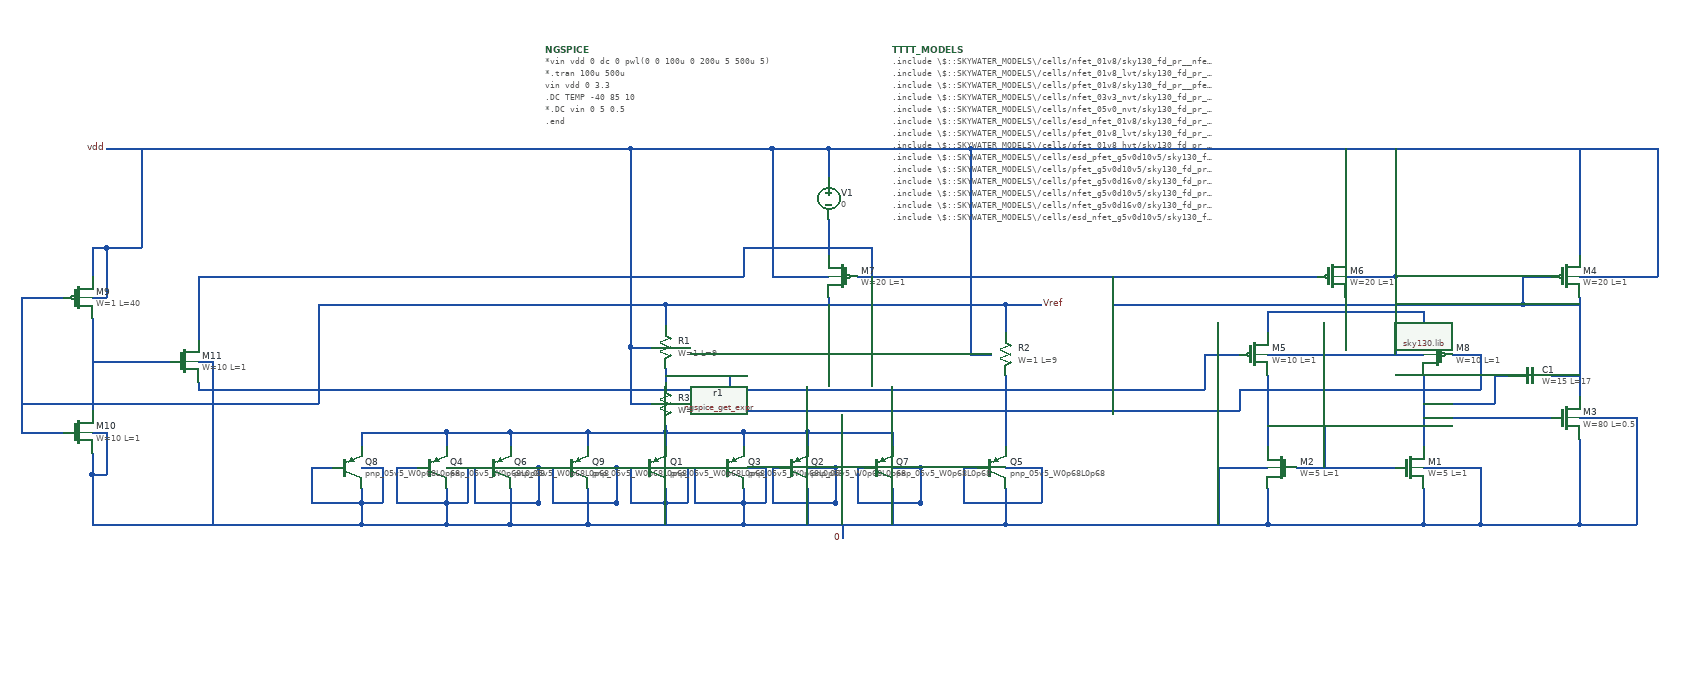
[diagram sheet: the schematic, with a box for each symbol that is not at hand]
v {xschem version=2.9.9 file_version=1.2 }
G {}
K {}
V {}
S {}
E {}
N 3560 -1290 3670 -1290 { lab=0}
N 3970 -1370 4110 -1370 { lab=#net1}
N 3930 -1470 3930 -1400 { lab=#net1}
N 4150 -1470 4150 -1400 { lab=#net2}
N 4010 -1430 4010 -1370 { lab=#net1}
N 3930 -1430 4010 -1430 { lab=#net1}
N 4150 -1340 4150 -1290 { lab=0}
N 3930 -1290 4150 -1290 { lab=0}
N 3930 -1340 3930 -1290 { lab=0}
N 4150 -1500 4150 -1470 { lab=#net2}
N 3930 -1500 3930 -1470 { lab=#net1}
N 4150 -1590 4150 -1560 { lab=#net3}
N 3930 -1590 4150 -1590 { lab=#net3}
N 3930 -1590 3930 -1560 { lab=#net3}
N 4040 -1610 4040 -1590 { lab=#net3}
N 3930 -1530 3980 -1530 { lab=vdd}
N 3980 -1530 4150 -1530 { lab=vdd}
N 4150 -1370 4190 -1370 { lab=0}
N 3810 -1290 3930 -1290 { lab=0}
N 3860 -1370 3930 -1370 { lab=0}
N 3860 -1370 3860 -1290 { lab=0}
N 4190 -1370 4230 -1370 { lab=0}
N 4230 -1370 4230 -1300 { lab=0}
N 4230 -1300 4230 -1290 { lab=0}
N 4150 -1290 4230 -1290 { lab=0}
N 4150 -1440 4330 -1440 { lab=#net2}
N 3080 -1510 3080 -1490 { lab=#net4}
N 3080 -1600 3370 -1600 { lab=Vref}
N 4370 -1410 4370 -1290 { lab=0}
N 4230 -1290 4370 -1290 { lab=0}
N 4450 -1440 4450 -1290 { lab=0}
N 4370 -1610 4370 -1470 { lab=#net5}
N 4370 -1640 4480 -1640 { lab=vdd}
N 4480 -1720 4480 -1640 { lab=vdd}
N 4370 -1720 4370 -1670 { lab=vdd}
N 4040 -1720 4040 -1670 { lab=vdd}
N 4230 -1530 4230 -1480 { lab=#net4}
N 4190 -1530 4230 -1530 { lab=#net4}
N 3840 -1530 3890 -1530 { lab=#net6}
N 3560 -1600 3610 -1600 { lab=Vref}
N 4330 -1500 4370 -1500 { lab=#net5}
N 4040 -1640 4110 -1640 { lab=vdd}
N 4110 -1640 4110 -1530 { lab=vdd}
N 4110 -1720 4110 -1640 { lab=vdd}
N 4290 -1640 4340 -1640 { lab=#net5}
N 3710 -1600 4290 -1600 { lab=#net5}
N 3080 -1600 3080 -1590 { lab=Vref}
N 3080 -1590 3080 -1570 { lab=Vref}
N 3560 -1500 3560 -1460 { lab=#net6}
N 3560 -1600 3560 -1560 { lab=Vref}
N 3190 -1370 3220 -1370 { lab=0}
N 3220 -1370 3220 -1320 { lab=0}
N 3190 -1320 3220 -1320 { lab=0}
N 3190 -1340 3190 -1320 { lab=0}
N 3190 -1320 3190 -1290 { lab=0}
N 3370 -1600 3560 -1600 { lab=Vref}
N 3560 -1460 3560 -1400 { lab=#net6}
N 3500 -1370 3520 -1370 { lab=0}
N 3500 -1370 3500 -1320 { lab=0}
N 3500 -1320 3610 -1320 { lab=0}
N 3610 -1370 3610 -1320 { lab=0}
N 3560 -1370 3610 -1370 { lab=0}
N 3560 -1340 3560 -1320 { lab=0}
N 3560 -1320 3560 -1290 { lab=0}
N 3190 -1420 3190 -1400 { lab=#net7}
N 3840 -1530 3840 -1480 { lab=#net6}
N 3890 -1480 4230 -1480 { lab=#net4}
N 3890 -1480 3890 -1450 { lab=#net4}
N 3170 -1450 3890 -1450 { lab=#net4}
N 3170 -1500 3170 -1450 { lab=#net4}
N 3080 -1500 3170 -1500 { lab=#net4}
N 3310 -1610 3310 -1600 { lab=Vref}
N 3350 -1640 4000 -1640 { lab=#net5}
N 4290 -1600 4370 -1600 { lab=#net5}
N 4290 -1640 4290 -1600 { lab=#net5}
N 4370 -1440 4450 -1440 { lab=0}
N 4370 -1290 4450 -1290 { lab=0}
N 3230 -1640 3310 -1640 { lab=vdd}
N 3230 -1720 3230 -1640 { lab=vdd}
N 3710 -1640 3710 -1600 { lab=#net5}
N 2920 -1370 2930 -1370 { lab=0}
N 2920 -1370 2920 -1320 { lab=0}
N 2920 -1320 3010 -1320 { lab=0}
N 3010 -1370 3010 -1320 { lab=0}
N 2970 -1370 3010 -1370 { lab=0}
N 2970 -1340 2970 -1320 { lab=0}
N 2970 -1320 2970 -1290 { lab=0}
N 2970 -1420 2970 -1400 { lab=#net7}
N 2970 -1420 3080 -1420 { lab=#net7}
N 3120 -1370 3150 -1370 { lab=0}
N 3120 -1370 3120 -1320 { lab=0}
N 3120 -1320 3190 -1320 { lab=0}
N 2970 -1290 3190 -1290 { lab=0}
N 3080 -1420 3190 -1420 { lab=#net7}
N 3080 -1430 3080 -1420 { lab=#net7}
N 3190 -1290 3560 -1290 { lab=0}
N 3330 -1290 3330 -1270 { lab=0}
N 3080 -1370 3110 -1370 { lab=0}
N 3110 -1370 3110 -1320 { lab=0}
N 3080 -1320 3110 -1320 { lab=0}
N 3080 -1340 3080 -1320 { lab=0}
N 3080 -1320 3080 -1290 { lab=0}
N 3080 -1420 3080 -1400 { lab=#net7}
N 3010 -1370 3010 -1320 { lab=0}
N 3030 -1370 3040 -1370 { lab=0}
N 3030 -1370 3030 -1320 { lab=0}
N 3030 -1320 3080 -1320 { lab=0}
N 3230 -1370 3240 -1370 { lab=0}
N 3230 -1370 3230 -1320 { lab=0}
N 3230 -1320 3320 -1320 { lab=0}
N 3320 -1370 3320 -1320 { lab=0}
N 3280 -1370 3320 -1370 { lab=0}
N 3280 -1340 3280 -1320 { lab=0}
N 3280 -1320 3280 -1290 { lab=0}
N 3280 -1420 3280 -1400 { lab=#net7}
N 3320 -1370 3320 -1320 { lab=0}
N 3190 -1420 3280 -1420 { lab=#net7}
N 2770 -1370 2800 -1370 { lab=0}
N 2800 -1370 2800 -1320 { lab=0}
N 2770 -1320 2800 -1320 { lab=0}
N 2770 -1340 2770 -1320 { lab=0}
N 2770 -1320 2770 -1290 { lab=0}
N 2770 -1420 2770 -1400 { lab=#net7}
N 2700 -1370 2730 -1370 { lab=0}
N 2700 -1370 2700 -1320 { lab=0}
N 2700 -1320 2770 -1320 { lab=0}
N 2810 -1370 2820 -1370 { lab=0}
N 2810 -1370 2810 -1320 { lab=0}
N 2810 -1320 2900 -1320 { lab=0}
N 2900 -1370 2900 -1320 { lab=0}
N 2860 -1370 2900 -1370 { lab=0}
N 2860 -1340 2860 -1320 { lab=0}
N 2860 -1320 2860 -1290 { lab=0}
N 2860 -1420 2860 -1400 { lab=#net7}
N 2900 -1370 2900 -1320 { lab=0}
N 2770 -1420 2860 -1420 { lab=#net7}
N 2860 -1290 2970 -1290 { lab=0}
N 2770 -1290 2860 -1290 { lab=0}
N 3350 -1370 3360 -1370 { lab=0}
N 3350 -1370 3350 -1320 { lab=0}
N 3350 -1320 3440 -1320 { lab=0}
N 3440 -1370 3440 -1320 { lab=0}
N 3400 -1370 3440 -1370 { lab=0}
N 3400 -1340 3400 -1320 { lab=0}
N 3400 -1420 3400 -1400 { lab=#net7}
N 3440 -1370 3440 -1320 { lab=0}
N 3400 -1320 3400 -1290 { lab=0}
N 3280 -1420 3400 -1420 { lab=#net7}
N 2860 -1420 2970 -1420 { lab=#net7}
N 2650 -1370 2680 -1370 { lab=0}
N 2680 -1370 2680 -1320 { lab=0}
N 2650 -1320 2680 -1320 { lab=0}
N 2650 -1340 2650 -1320 { lab=0}
N 2650 -1320 2650 -1290 { lab=0}
N 2650 -1420 2650 -1400 { lab=#net7}
N 2580 -1370 2610 -1370 { lab=0}
N 2580 -1370 2580 -1320 { lab=0}
N 2580 -1320 2650 -1320 { lab=0}
N 2650 -1420 2770 -1420 { lab=#net7}
N 2650 -1290 2770 -1290 { lab=0}
N 2170 -1610 2230 -1610 { lab=Vref}
N 2170 -1610 2170 -1420 { lab=Vref}
N 2170 -1420 2230 -1420 { lab=Vref}
N 2270 -1580 2270 -1450 { lab=#net8}
N 2270 -1610 2290 -1610 { lab=vdd}
N 2290 -1680 2290 -1610 { lab=vdd}
N 2270 -1680 2290 -1680 { lab=vdd}
N 2270 -1680 2270 -1640 { lab=vdd}
N 2270 -1420 2290 -1420 { lab=0}
N 2290 -1420 2290 -1360 { lab=0}
N 2270 -1360 2290 -1360 { lab=0}
N 2270 -1390 2270 -1360 { lab=0}
N 2270 -1360 2270 -1300 { lab=0}
N 2270 -1300 2270 -1290 { lab=0}
N 2270 -1290 2650 -1290 { lab=0}
N 2420 -1640 2420 -1550 { lab=#net5}
N 2420 -1640 3190 -1640 { lab=#net5}
N 3190 -1680 3190 -1640 { lab=#net5}
N 3190 -1680 3370 -1680 { lab=#net5}
N 3370 -1680 3370 -1640 { lab=#net5}
N 2420 -1520 2440 -1520 { lab=0}
N 2440 -1520 2440 -1290 { lab=0}
N 2420 -1460 2590 -1460 { lab=Vref}
N 2590 -1600 2590 -1460 { lab=Vref}
N 2590 -1600 3080 -1600 { lab=Vref}
N 2270 -1520 2380 -1520 { lab=#net8}
N 2170 -1460 2420 -1460 { lab=Vref}
N 2420 -1480 3560 -1480 { lab=#net6}
N 2420 -1490 2420 -1480 { lab=#net6}
N 3510 -1530 3540 -1530 { lab=vdd}
N 3510 -1720 3510 -1530 { lab=vdd}
N 3030 -1540 3060 -1540 { lab=vdd}
N 3030 -1460 3060 -1460 { lab=vdd}
N 3030 -1540 3030 -1460 { lab=vdd}
N 4150 -1460 4250 -1460 { lab=#net2}
N 4250 -1500 4250 -1460 { lab=#net2}
N 4250 -1500 4270 -1500 { lab=#net2}
N 3670 -1290 3810 -1290 { lab=0}
N 3560 -1480 3680 -1480 { lab=#net6}
N 3680 -1480 3840 -1480 { lab=#net6}
N 3030 -1820 3030 -1540 { lab=vdd}
N 2290 -1820 3030 -1820 { lab=vdd}
N 2290 -1680 2340 -1680 { lab=vdd}
N 2340 -1820 2340 -1680 { lab=vdd}
N 3230 -1820 3230 -1720 { lab=vdd}
N 3030 -1820 3230 -1820 { lab=vdd}
N 3310 -1720 3310 -1670 { lab=#net9}
N 3310 -1820 3310 -1780 { lab=vdd}
N 3230 -1820 3310 -1820 { lab=vdd}
N 3510 -1820 3510 -1720 { lab=vdd}
N 3310 -1820 3510 -1820 { lab=vdd}
N 3510 -1820 4480 -1820 { lab=vdd}
N 4480 -1820 4480 -1720 { lab=vdd}
N 4370 -1820 4370 -1720 { lab=vdd}
N 4110 -1820 4110 -1720 { lab=vdd}
N 4040 -1820 4040 -1720 { lab=vdd}
C {sky130_fd_pr/pnp_05v5.sym} 3170 -1370 0 0 {name=Q3
model=pnp_05v5_W0p68L0p68
spiceprefix=X
}
C {devices/lab_pin.sym} 3610 -1600 0 1 {name=l4 sig_type=std_logic lab=Vref}
C {devices/code_shown.sym} 2910 -1960 0 0 {name=NGSPICE
only_toplevel=true
value="
*vin vdd 0 dc 0 pwl(0 0 100u 0 200u 5 500u 5)
*.tran 100u 500u
vin vdd 0 3.3
.DC TEMP -40 85 10
*.DC vin 0 5 0.5
.end
" }
C {sky130_fd_pr/pnp_05v5.sym} 3540 -1370 0 0 {name=Q5
model=pnp_05v5_W0p68L0p68
spiceprefix=X
}
C {devices/lab_pin.sym} 2290 -1820 0 0 {name=l2 sig_type=std_logic lab=vdd}
C {sky130_fd_pr/pnp_05v5.sym} 2950 -1370 0 0 {name=Q9
model=pnp_05v5_W0p68L0p68
spiceprefix=X
}
C {devices/lab_pin.sym} 3330 -1270 0 0 {name=l1 sig_type=std_logic lab=0}
C {sky130_fd_pr/pnp_05v5.sym} 3060 -1370 0 0 {name=Q1
model=pnp_05v5_W0p68L0p68
spiceprefix=X
}
C {sky130_fd_pr/pnp_05v5.sym} 3260 -1370 0 0 {name=Q2
model=pnp_05v5_W0p68L0p68
spiceprefix=X
}
C {sky130_fd_pr/pnp_05v5.sym} 2750 -1370 0 0 {name=Q4
model=pnp_05v5_W0p68L0p68
spiceprefix=X
}
C {sky130_fd_pr/pnp_05v5.sym} 2840 -1370 0 0 {name=Q6
model=pnp_05v5_W0p68L0p68
spiceprefix=X
}
C {sky130_fd_pr/pnp_05v5.sym} 3380 -1370 0 0 {name=Q7
model=pnp_05v5_W0p68L0p68
spiceprefix=X
}
C {sky130_fd_pr/pnp_05v5.sym} 2630 -1370 0 0 {name=Q8
model=pnp_05v5_W0p68L0p68
spiceprefix=X
}
C {sky130_fd_pr/nfet_g5v0d10v5.sym} 4130 -1370 0 0 {name=M1
L=1
W=5
nf=1
mult=1
ad="'int((nf+1)/2) * W/nf * 0.29'" 
pd="'2*int((nf+1)/2) * (W/nf + 0.29)'"
as="'int((nf+2)/2) * W/nf * 0.29'" 
ps="'2*int((nf+2)/2) * (W/nf + 0.29)'"
nrd="'0.29 / W'" nrs="'0.29 / W'"
sa=0 sb=0 sd=0
model=nfet_g5v0d10v5
spiceprefix=X
}
C {sky130_fd_pr/nfet_g5v0d10v5.sym} 3950 -1370 0 1 {name=M2
L=1
W=5
nf=1
mult=1
ad="'int((nf+1)/2) * W/nf * 0.29'" 
pd="'2*int((nf+1)/2) * (W/nf + 0.29)'"
as="'int((nf+2)/2) * W/nf * 0.29'" 
ps="'2*int((nf+2)/2) * (W/nf + 0.29)'"
nrd="'0.29 / W'" nrs="'0.29 / W'"
sa=0 sb=0 sd=0
model=nfet_g5v0d10v5
spiceprefix=X
}
C {sky130_fd_pr/nfet_g5v0d10v5.sym} 4350 -1440 0 0 {name=M3
L=0.5
W=80
nf=1
mult=10
ad="'int((nf+1)/2) * W/nf * 0.29'" 
pd="'2*int((nf+1)/2) * (W/nf + 0.29)'"
as="'int((nf+2)/2) * W/nf * 0.29'" 
ps="'2*int((nf+2)/2) * (W/nf + 0.29)'"
nrd="'0.29 / W'" nrs="'0.29 / W'"
sa=0 sb=0 sd=0
model=nfet_g5v0d10v5
spiceprefix=X
}
C {sky130_fd_pr/pfet_g5v0d10v5.sym} 4350 -1640 0 0 {name=M4
L=1
W=20
nf=1
mult=1
ad="'int((nf+1)/2) * W/nf * 0.29'" 
pd="'2*int((nf+1)/2) * (W/nf + 0.29)'"
as="'int((nf+2)/2) * W/nf * 0.29'" 
ps="'2*int((nf+2)/2) * (W/nf + 0.29)'"
nrd="'0.29 / W'" nrs="'0.29 / W'"
sa=0 sb=0 sd=0
model=pfet_g5v0d10v5
spiceprefix=X
}
C {sky130_fd_pr/pfet_g5v0d10v5.sym} 3910 -1530 0 0 {name=M5
L=1
W=10
nf=1
mult=1
ad="'int((nf+1)/2) * W/nf * 0.29'" 
pd="'2*int((nf+1)/2) * (W/nf + 0.29)'"
as="'int((nf+2)/2) * W/nf * 0.29'" 
ps="'2*int((nf+2)/2) * (W/nf + 0.29)'"
nrd="'0.29 / W'" nrs="'0.29 / W'"
sa=0 sb=0 sd=0
model=pfet_g5v0d10v5
spiceprefix=X
}
C {sky130_fd_pr/pfet_g5v0d10v5.sym} 4020 -1640 0 0 {name=M6
L=1
W=20
nf=1
mult=1
ad="'int((nf+1)/2) * W/nf * 0.29'" 
pd="'2*int((nf+1)/2) * (W/nf + 0.29)'"
as="'int((nf+2)/2) * W/nf * 0.29'" 
ps="'2*int((nf+2)/2) * (W/nf + 0.29)'"
nrd="'0.29 / W'" nrs="'0.29 / W'"
sa=0 sb=0 sd=0
model=pfet_g5v0d10v5
spiceprefix=X
}
C {sky130_fd_pr/pfet_g5v0d10v5.sym} 3330 -1640 0 1 {name=M7
L=1
W=20
nf=1
mult=1
ad="'int((nf+1)/2) * W/nf * 0.29'" 
pd="'2*int((nf+1)/2) * (W/nf + 0.29)'"
as="'int((nf+2)/2) * W/nf * 0.29'" 
ps="'2*int((nf+2)/2) * (W/nf + 0.29)'"
nrd="'0.29 / W'" nrs="'0.29 / W'"
sa=0 sb=0 sd=0
model=pfet_g5v0d10v5
spiceprefix=X
}
C {sky130_fd_pr/pfet_g5v0d10v5.sym} 4170 -1530 0 1 {name=M8
L=1
W=10
nf=1
mult=1
ad="'int((nf+1)/2) * W/nf * 0.29'" 
pd="'2*int((nf+1)/2) * (W/nf + 0.29)'"
as="'int((nf+2)/2) * W/nf * 0.29'" 
ps="'2*int((nf+2)/2) * (W/nf + 0.29)'"
nrd="'0.29 / W'" nrs="'0.29 / W'"
sa=0 sb=0 sd=0
model=pfet_g5v0d10v5
spiceprefix=X
}
C {sky130_fd_pr/pfet_g5v0d10v5.sym} 2250 -1610 0 0 {name=M9
L=40
W=1
nf=1
mult=1
ad="'int((nf+1)/2) * W/nf * 0.29'" 
pd="'2*int((nf+1)/2) * (W/nf + 0.29)'"
as="'int((nf+2)/2) * W/nf * 0.29'" 
ps="'2*int((nf+2)/2) * (W/nf + 0.29)'"
nrd="'0.29 / W'" nrs="'0.29 / W'"
sa=0 sb=0 sd=0
model=pfet_g5v0d10v5
spiceprefix=X
}
C {sky130_fd_pr/nfet_g5v0d10v5.sym} 2250 -1420 0 0 {name=M10
L=1
W=10
nf=1
mult=1
ad="'int((nf+1)/2) * W/nf * 0.29'" 
pd="'2*int((nf+1)/2) * (W/nf + 0.29)'"
as="'int((nf+2)/2) * W/nf * 0.29'" 
ps="'2*int((nf+2)/2) * (W/nf + 0.29)'"
nrd="'0.29 / W'" nrs="'0.29 / W'"
sa=0 sb=0 sd=0
model=nfet_g5v0d10v5
spiceprefix=X
}
C {sky130_fd_pr/nfet_g5v0d10v5.sym} 2400 -1520 0 0 {name=M11
L=1
W=10
nf=1
mult=1
ad="'int((nf+1)/2) * W/nf * 0.29'" 
pd="'2*int((nf+1)/2) * (W/nf + 0.29)'"
as="'int((nf+2)/2) * W/nf * 0.29'" 
ps="'2*int((nf+2)/2) * (W/nf + 0.29)'"
nrd="'0.29 / W'" nrs="'0.29 / W'"
sa=0 sb=0 sd=0
model=nfet_g5v0d10v5
spiceprefix=X
}
C {sky130_fd_pr/res_xhigh_po.sym} 3080 -1540 0 0 {name=R1
W=1
L=9
model=res_xhigh_po
spiceprefix=X
mult=1}
C {sky130_fd_pr/res_xhigh_po.sym} 3560 -1530 0 0 {name=R2
W=1
L=9
model=res_xhigh_po
spiceprefix=X
mult=1}
C {sky130_fd_pr/res_xhigh_po.sym} 3080 -1460 0 0 {name=R3
W=1
L=2.5
model=res_xhigh_po
spiceprefix=X
mult=1}
C {sky130_fd_pr_ngspice/latest/models/sky130.lib.spice} 4080 -1130 0 0 {}
C {devices/code.sym} 3400 -1960 0 0 {name=TTTT_MODELS
spice_ignore=false
only_toplevel=true
format="tcleval( @value )"
value="
.include \\\\$::SKYWATER_MODELS\\\\/cells/nfet_01v8/sky130_fd_pr__nfet_01v8__tt.corner.spice
.include \\\\$::SKYWATER_MODELS\\\\/cells/nfet_01v8_lvt/sky130_fd_pr__nfet_01v8_lvt__tt.corner.spice
.include \\\\$::SKYWATER_MODELS\\\\/cells/pfet_01v8/sky130_fd_pr__pfet_01v8__tt.corner.spice
.include \\\\$::SKYWATER_MODELS\\\\/cells/nfet_03v3_nvt/sky130_fd_pr__nfet_03v3_nvt__tt.corner.spice
.include \\\\$::SKYWATER_MODELS\\\\/cells/nfet_05v0_nvt/sky130_fd_pr__nfet_05v0_nvt__tt.corner.spice
.include \\\\$::SKYWATER_MODELS\\\\/cells/esd_nfet_01v8/sky130_fd_pr__esd_nfet_01v8__tt.corner.spice
.include \\\\$::SKYWATER_MODELS\\\\/cells/pfet_01v8_lvt/sky130_fd_pr__pfet_01v8_lvt__tt.corner.spice
.include \\\\$::SKYWATER_MODELS\\\\/cells/pfet_01v8_hvt/sky130_fd_pr__pfet_01v8_hvt__tt.corner.spice
.include \\\\$::SKYWATER_MODELS\\\\/cells/esd_pfet_g5v0d10v5/sky130_fd_pr__esd_pfet_g5v0d10v5__tt.corner.spice
.include \\\\$::SKYWATER_MODELS\\\\/cells/pfet_g5v0d10v5/sky130_fd_pr__pfet_g5v0d10v5__tt.corner.spice
.include \\\\$::SKYWATER_MODELS\\\\/cells/pfet_g5v0d16v0/sky130_fd_pr__pfet_g5v0d16v0__tt.corner.spice
.include \\\\$::SKYWATER_MODELS\\\\/cells/nfet_g5v0d10v5/sky130_fd_pr__nfet_g5v0d10v5__tt.corner.spice
.include \\\\$::SKYWATER_MODELS\\\\/cells/nfet_g5v0d16v0/sky130_fd_pr__nfet_g5v0d16v0__tt_discrete.corner.spice
.include \\\\$::SKYWATER_MODELS\\\\/cells/esd_nfet_g5v0d10v5/sky130_fd_pr__esd_nfet_g5v0d10v5__tt.corner.spice
.include \\\\$::SKYWATER_MODELS\\\\/models/corners/tt/nonfet.spice
* Mismatch parameters
.include \\\\$::SKYWATER_MODELS\\\\/cells/nfet_01v8/sky130_fd_pr__nfet_01v8__mismatch.corner.spice
.include \\\\$::SKYWATER_MODELS\\\\/cells/pfet_01v8/sky130_fd_pr__pfet_01v8__mismatch.corner.spice
.include \\\\$::SKYWATER_MODELS\\\\/cells/nfet_01v8_lvt/sky130_fd_pr__nfet_01v8_lvt__mismatch.corner.spice
.include \\\\$::SKYWATER_MODELS\\\\/cells/pfet_01v8_lvt/sky130_fd_pr__pfet_01v8_lvt__mismatch.corner.spice
.include \\\\$::SKYWATER_MODELS\\\\/cells/pfet_01v8_hvt/sky130_fd_pr__pfet_01v8_hvt__mismatch.corner.spice
.include \\\\$::SKYWATER_MODELS\\\\/cells/nfet_g5v0d10v5/sky130_fd_pr__nfet_g5v0d10v5__mismatch.corner.spice
.include \\\\$::SKYWATER_MODELS\\\\/cells/pfet_g5v0d10v5/sky130_fd_pr__pfet_g5v0d10v5__mismatch.corner.spice
.include \\\\$::SKYWATER_MODELS\\\\/cells/nfet_05v0_nvt/sky130_fd_pr__nfet_05v0_nvt__mismatch.corner.spice
.include \\\\$::SKYWATER_MODELS\\\\/cells/nfet_03v3_nvt/sky130_fd_pr__nfet_03v3_nvt__mismatch.corner.spice
* Resistor\\\\$::SKYWATER_MODELS\\\\/Capacitor
.include \\\\$::SKYWATER_MODELS\\\\/models/r+c/res_typical__cap_typical.spice
.include \\\\$::SKYWATER_MODELS\\\\/models/r+c/res_typical__cap_typical__lin.spice
* Special cells
.include \\\\$::SKYWATER_MODELS\\\\/models/corners/tt/specialized_cells.spice
* All models
.include \\\\$::SKYWATER_MODELS\\\\/models/all.spice
* Corner
.include \\\\$::SKYWATER_MODELS\\\\/models/corners/tt/rf.spice
"}
C {sky130_fd_pr/cap_mim_m3_2.sym} 4300 -1500 3 0 {name=C1 model=cap_mim_m3_2 W=15 L=17 MF=1 spiceprefix=X}
C {devices/vsource.sym} 3310 -1750 0 0 {name=V1 value=0}
C {devices/ngspice_get_expr.sym} 3270 -1740 0 0 {name=r1 node="[ngspice::get_current V1]"}
